VERSION 5.7 ;
BUSBITCHARS "[]" ;
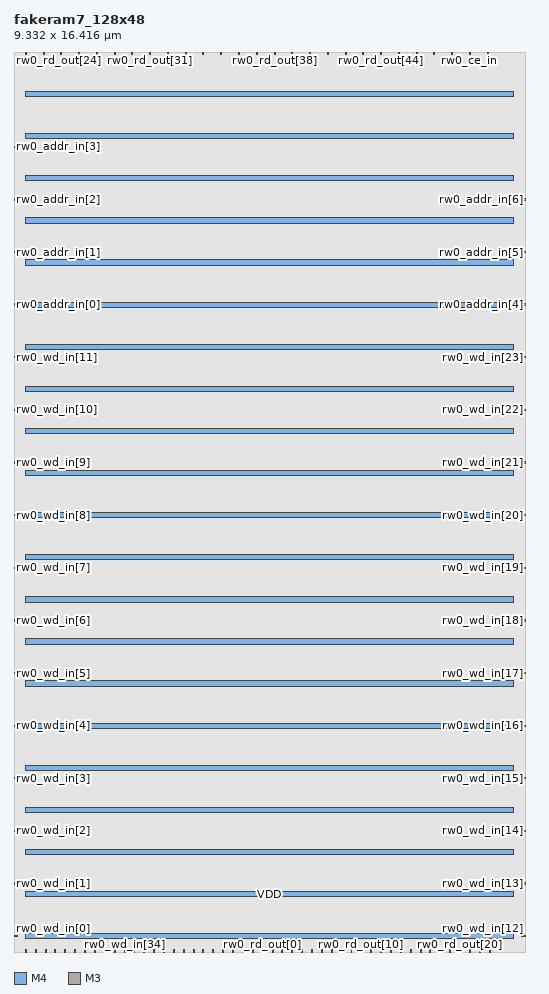
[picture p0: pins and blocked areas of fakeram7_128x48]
MACRO fakeram7_128x48
  FOREIGN fakeram7_128x48 0 0 ;
  SYMMETRY X Y R90 ;
  SIZE 9.332 BY 16.416 ;
  CLASS BLOCK ;
  PIN rw0_wd_in[0]
    DIRECTION INPUT ;
    USE SIGNAL ;
    SHAPE ABUTMENT ;
    PORT
      LAYER M4 ;
      RECT 0.000 0.276 0.072 0.300 ;
    END
  END rw0_wd_in[0]
  PIN rw0_wd_in[1]
    DIRECTION INPUT ;
    USE SIGNAL ;
    SHAPE ABUTMENT ;
    PORT
      LAYER M4 ;
      RECT 0.000 1.236 0.072 1.260 ;
    END
  END rw0_wd_in[1]
  PIN rw0_wd_in[2]
    DIRECTION INPUT ;
    USE SIGNAL ;
    SHAPE ABUTMENT ;
    PORT
      LAYER M4 ;
      RECT 0.000 2.196 0.072 2.220 ;
    END
  END rw0_wd_in[2]
  PIN rw0_wd_in[3]
    DIRECTION INPUT ;
    USE SIGNAL ;
    SHAPE ABUTMENT ;
    PORT
      LAYER M4 ;
      RECT 0.000 3.156 0.072 3.180 ;
    END
  END rw0_wd_in[3]
  PIN rw0_wd_in[4]
    DIRECTION INPUT ;
    USE SIGNAL ;
    SHAPE ABUTMENT ;
    PORT
      LAYER M4 ;
      RECT 0.000 4.116 0.072 4.140 ;
    END
  END rw0_wd_in[4]
  PIN rw0_wd_in[5]
    DIRECTION INPUT ;
    USE SIGNAL ;
    SHAPE ABUTMENT ;
    PORT
      LAYER M4 ;
      RECT 0.000 5.076 0.072 5.100 ;
    END
  END rw0_wd_in[5]
  PIN rw0_wd_in[6]
    DIRECTION INPUT ;
    USE SIGNAL ;
    SHAPE ABUTMENT ;
    PORT
      LAYER M4 ;
      RECT 0.000 6.036 0.072 6.060 ;
    END
  END rw0_wd_in[6]
  PIN rw0_wd_in[7]
    DIRECTION INPUT ;
    USE SIGNAL ;
    SHAPE ABUTMENT ;
    PORT
      LAYER M4 ;
      RECT 0.000 6.996 0.072 7.020 ;
    END
  END rw0_wd_in[7]
  PIN rw0_wd_in[8]
    DIRECTION INPUT ;
    USE SIGNAL ;
    SHAPE ABUTMENT ;
    PORT
      LAYER M4 ;
      RECT 0.000 7.956 0.072 7.980 ;
    END
  END rw0_wd_in[8]
  PIN rw0_wd_in[9]
    DIRECTION INPUT ;
    USE SIGNAL ;
    SHAPE ABUTMENT ;
    PORT
      LAYER M4 ;
      RECT 0.000 8.916 0.072 8.940 ;
    END
  END rw0_wd_in[9]
  PIN rw0_wd_in[10]
    DIRECTION INPUT ;
    USE SIGNAL ;
    SHAPE ABUTMENT ;
    PORT
      LAYER M4 ;
      RECT 0.000 9.876 0.072 9.900 ;
    END
  END rw0_wd_in[10]
  PIN rw0_wd_in[11]
    DIRECTION INPUT ;
    USE SIGNAL ;
    SHAPE ABUTMENT ;
    PORT
      LAYER M4 ;
      RECT 0.000 10.836 0.072 10.860 ;
    END
  END rw0_wd_in[11]
  PIN rw0_wd_in[12]
    DIRECTION INPUT ;
    USE SIGNAL ;
    SHAPE ABUTMENT ;
    PORT
      LAYER M4 ;
      RECT 9.260 0.276 9.332 0.300 ;
    END
  END rw0_wd_in[12]
  PIN rw0_wd_in[13]
    DIRECTION INPUT ;
    USE SIGNAL ;
    SHAPE ABUTMENT ;
    PORT
      LAYER M4 ;
      RECT 9.260 1.236 9.332 1.260 ;
    END
  END rw0_wd_in[13]
  PIN rw0_wd_in[14]
    DIRECTION INPUT ;
    USE SIGNAL ;
    SHAPE ABUTMENT ;
    PORT
      LAYER M4 ;
      RECT 9.260 2.196 9.332 2.220 ;
    END
  END rw0_wd_in[14]
  PIN rw0_wd_in[15]
    DIRECTION INPUT ;
    USE SIGNAL ;
    SHAPE ABUTMENT ;
    PORT
      LAYER M4 ;
      RECT 9.260 3.156 9.332 3.180 ;
    END
  END rw0_wd_in[15]
  PIN rw0_wd_in[16]
    DIRECTION INPUT ;
    USE SIGNAL ;
    SHAPE ABUTMENT ;
    PORT
      LAYER M4 ;
      RECT 9.260 4.116 9.332 4.140 ;
    END
  END rw0_wd_in[16]
  PIN rw0_wd_in[17]
    DIRECTION INPUT ;
    USE SIGNAL ;
    SHAPE ABUTMENT ;
    PORT
      LAYER M4 ;
      RECT 9.260 5.076 9.332 5.100 ;
    END
  END rw0_wd_in[17]
  PIN rw0_wd_in[18]
    DIRECTION INPUT ;
    USE SIGNAL ;
    SHAPE ABUTMENT ;
    PORT
      LAYER M4 ;
      RECT 9.260 6.036 9.332 6.060 ;
    END
  END rw0_wd_in[18]
  PIN rw0_wd_in[19]
    DIRECTION INPUT ;
    USE SIGNAL ;
    SHAPE ABUTMENT ;
    PORT
      LAYER M4 ;
      RECT 9.260 6.996 9.332 7.020 ;
    END
  END rw0_wd_in[19]
  PIN rw0_wd_in[20]
    DIRECTION INPUT ;
    USE SIGNAL ;
    SHAPE ABUTMENT ;
    PORT
      LAYER M4 ;
      RECT 9.260 7.956 9.332 7.980 ;
    END
  END rw0_wd_in[20]
  PIN rw0_wd_in[21]
    DIRECTION INPUT ;
    USE SIGNAL ;
    SHAPE ABUTMENT ;
    PORT
      LAYER M4 ;
      RECT 9.260 8.916 9.332 8.940 ;
    END
  END rw0_wd_in[21]
  PIN rw0_wd_in[22]
    DIRECTION INPUT ;
    USE SIGNAL ;
    SHAPE ABUTMENT ;
    PORT
      LAYER M4 ;
      RECT 9.260 9.876 9.332 9.900 ;
    END
  END rw0_wd_in[22]
  PIN rw0_wd_in[23]
    DIRECTION INPUT ;
    USE SIGNAL ;
    SHAPE ABUTMENT ;
    PORT
      LAYER M4 ;
      RECT 9.260 10.836 9.332 10.860 ;
    END
  END rw0_wd_in[23]
  PIN rw0_wd_in[24]
    DIRECTION OUTPUT ;
    USE SIGNAL ;
    SHAPE ABUTMENT ;
    PORT
      LAYER M3 ;
      RECT 0.207 0.000 0.225 0.054 ;
    END
  END rw0_wd_in[24]
  PIN rw0_wd_in[25]
    DIRECTION OUTPUT ;
    USE SIGNAL ;
    SHAPE ABUTMENT ;
    PORT
      LAYER M3 ;
      RECT 0.387 0.000 0.405 0.054 ;
    END
  END rw0_wd_in[25]
  PIN rw0_wd_in[26]
    DIRECTION OUTPUT ;
    USE SIGNAL ;
    SHAPE ABUTMENT ;
    PORT
      LAYER M3 ;
      RECT 0.567 0.000 0.585 0.054 ;
    END
  END rw0_wd_in[26]
  PIN rw0_wd_in[27]
    DIRECTION OUTPUT ;
    USE SIGNAL ;
    SHAPE ABUTMENT ;
    PORT
      LAYER M3 ;
      RECT 0.747 0.000 0.765 0.054 ;
    END
  END rw0_wd_in[27]
  PIN rw0_wd_in[28]
    DIRECTION OUTPUT ;
    USE SIGNAL ;
    SHAPE ABUTMENT ;
    PORT
      LAYER M3 ;
      RECT 0.927 0.000 0.945 0.054 ;
    END
  END rw0_wd_in[28]
  PIN rw0_wd_in[29]
    DIRECTION OUTPUT ;
    USE SIGNAL ;
    SHAPE ABUTMENT ;
    PORT
      LAYER M3 ;
      RECT 1.107 0.000 1.125 0.054 ;
    END
  END rw0_wd_in[29]
  PIN rw0_wd_in[30]
    DIRECTION OUTPUT ;
    USE SIGNAL ;
    SHAPE ABUTMENT ;
    PORT
      LAYER M3 ;
      RECT 1.287 0.000 1.305 0.054 ;
    END
  END rw0_wd_in[30]
  PIN rw0_wd_in[31]
    DIRECTION OUTPUT ;
    USE SIGNAL ;
    SHAPE ABUTMENT ;
    PORT
      LAYER M3 ;
      RECT 1.467 0.000 1.485 0.054 ;
    END
  END rw0_wd_in[31]
  PIN rw0_wd_in[32]
    DIRECTION OUTPUT ;
    USE SIGNAL ;
    SHAPE ABUTMENT ;
    PORT
      LAYER M3 ;
      RECT 1.647 0.000 1.665 0.054 ;
    END
  END rw0_wd_in[32]
  PIN rw0_wd_in[33]
    DIRECTION OUTPUT ;
    USE SIGNAL ;
    SHAPE ABUTMENT ;
    PORT
      LAYER M3 ;
      RECT 1.827 0.000 1.845 0.054 ;
    END
  END rw0_wd_in[33]
  PIN rw0_wd_in[34]
    DIRECTION OUTPUT ;
    USE SIGNAL ;
    SHAPE ABUTMENT ;
    PORT
      LAYER M3 ;
      RECT 2.007 0.000 2.025 0.054 ;
    END
  END rw0_wd_in[34]
  PIN rw0_wd_in[35]
    DIRECTION OUTPUT ;
    USE SIGNAL ;
    SHAPE ABUTMENT ;
    PORT
      LAYER M3 ;
      RECT 2.187 0.000 2.205 0.054 ;
    END
  END rw0_wd_in[35]
  PIN rw0_wd_in[36]
    DIRECTION OUTPUT ;
    USE SIGNAL ;
    SHAPE ABUTMENT ;
    PORT
      LAYER M3 ;
      RECT 2.367 0.000 2.385 0.054 ;
    END
  END rw0_wd_in[36]
  PIN rw0_wd_in[37]
    DIRECTION OUTPUT ;
    USE SIGNAL ;
    SHAPE ABUTMENT ;
    PORT
      LAYER M3 ;
      RECT 2.547 0.000 2.565 0.054 ;
    END
  END rw0_wd_in[37]
  PIN rw0_wd_in[38]
    DIRECTION OUTPUT ;
    USE SIGNAL ;
    SHAPE ABUTMENT ;
    PORT
      LAYER M3 ;
      RECT 2.727 0.000 2.745 0.054 ;
    END
  END rw0_wd_in[38]
  PIN rw0_wd_in[39]
    DIRECTION OUTPUT ;
    USE SIGNAL ;
    SHAPE ABUTMENT ;
    PORT
      LAYER M3 ;
      RECT 2.907 0.000 2.925 0.054 ;
    END
  END rw0_wd_in[39]
  PIN rw0_wd_in[40]
    DIRECTION OUTPUT ;
    USE SIGNAL ;
    SHAPE ABUTMENT ;
    PORT
      LAYER M3 ;
      RECT 3.087 0.000 3.105 0.054 ;
    END
  END rw0_wd_in[40]
  PIN rw0_wd_in[41]
    DIRECTION OUTPUT ;
    USE SIGNAL ;
    SHAPE ABUTMENT ;
    PORT
      LAYER M3 ;
      RECT 3.267 0.000 3.285 0.054 ;
    END
  END rw0_wd_in[41]
  PIN rw0_wd_in[42]
    DIRECTION OUTPUT ;
    USE SIGNAL ;
    SHAPE ABUTMENT ;
    PORT
      LAYER M3 ;
      RECT 3.447 0.000 3.465 0.054 ;
    END
  END rw0_wd_in[42]
  PIN rw0_wd_in[43]
    DIRECTION OUTPUT ;
    USE SIGNAL ;
    SHAPE ABUTMENT ;
    PORT
      LAYER M3 ;
      RECT 3.627 0.000 3.645 0.054 ;
    END
  END rw0_wd_in[43]
  PIN rw0_wd_in[44]
    DIRECTION OUTPUT ;
    USE SIGNAL ;
    SHAPE ABUTMENT ;
    PORT
      LAYER M3 ;
      RECT 3.807 0.000 3.825 0.054 ;
    END
  END rw0_wd_in[44]
  PIN rw0_wd_in[45]
    DIRECTION OUTPUT ;
    USE SIGNAL ;
    SHAPE ABUTMENT ;
    PORT
      LAYER M3 ;
      RECT 3.987 0.000 4.005 0.054 ;
    END
  END rw0_wd_in[45]
  PIN rw0_wd_in[46]
    DIRECTION OUTPUT ;
    USE SIGNAL ;
    SHAPE ABUTMENT ;
    PORT
      LAYER M3 ;
      RECT 4.167 0.000 4.185 0.054 ;
    END
  END rw0_wd_in[46]
  PIN rw0_wd_in[47]
    DIRECTION OUTPUT ;
    USE SIGNAL ;
    SHAPE ABUTMENT ;
    PORT
      LAYER M3 ;
      RECT 4.347 0.000 4.365 0.054 ;
    END
  END rw0_wd_in[47]
  PIN rw0_rd_out[0]
    DIRECTION OUTPUT ;
    USE SIGNAL ;
    SHAPE ABUTMENT ;
    PORT
      LAYER M3 ;
      RECT 4.527 0.000 4.545 0.054 ;
    END
  END rw0_rd_out[0]
  PIN rw0_rd_out[1]
    DIRECTION OUTPUT ;
    USE SIGNAL ;
    SHAPE ABUTMENT ;
    PORT
      LAYER M3 ;
      RECT 4.707 0.000 4.725 0.054 ;
    END
  END rw0_rd_out[1]
  PIN rw0_rd_out[2]
    DIRECTION OUTPUT ;
    USE SIGNAL ;
    SHAPE ABUTMENT ;
    PORT
      LAYER M3 ;
      RECT 4.887 0.000 4.905 0.054 ;
    END
  END rw0_rd_out[2]
  PIN rw0_rd_out[3]
    DIRECTION OUTPUT ;
    USE SIGNAL ;
    SHAPE ABUTMENT ;
    PORT
      LAYER M3 ;
      RECT 5.067 0.000 5.085 0.054 ;
    END
  END rw0_rd_out[3]
  PIN rw0_rd_out[4]
    DIRECTION OUTPUT ;
    USE SIGNAL ;
    SHAPE ABUTMENT ;
    PORT
      LAYER M3 ;
      RECT 5.247 0.000 5.265 0.054 ;
    END
  END rw0_rd_out[4]
  PIN rw0_rd_out[5]
    DIRECTION OUTPUT ;
    USE SIGNAL ;
    SHAPE ABUTMENT ;
    PORT
      LAYER M3 ;
      RECT 5.427 0.000 5.445 0.054 ;
    END
  END rw0_rd_out[5]
  PIN rw0_rd_out[6]
    DIRECTION OUTPUT ;
    USE SIGNAL ;
    SHAPE ABUTMENT ;
    PORT
      LAYER M3 ;
      RECT 5.607 0.000 5.625 0.054 ;
    END
  END rw0_rd_out[6]
  PIN rw0_rd_out[7]
    DIRECTION OUTPUT ;
    USE SIGNAL ;
    SHAPE ABUTMENT ;
    PORT
      LAYER M3 ;
      RECT 5.787 0.000 5.805 0.054 ;
    END
  END rw0_rd_out[7]
  PIN rw0_rd_out[8]
    DIRECTION OUTPUT ;
    USE SIGNAL ;
    SHAPE ABUTMENT ;
    PORT
      LAYER M3 ;
      RECT 5.967 0.000 5.985 0.054 ;
    END
  END rw0_rd_out[8]
  PIN rw0_rd_out[9]
    DIRECTION OUTPUT ;
    USE SIGNAL ;
    SHAPE ABUTMENT ;
    PORT
      LAYER M3 ;
      RECT 6.147 0.000 6.165 0.054 ;
    END
  END rw0_rd_out[9]
  PIN rw0_rd_out[10]
    DIRECTION OUTPUT ;
    USE SIGNAL ;
    SHAPE ABUTMENT ;
    PORT
      LAYER M3 ;
      RECT 6.327 0.000 6.345 0.054 ;
    END
  END rw0_rd_out[10]
  PIN rw0_rd_out[11]
    DIRECTION OUTPUT ;
    USE SIGNAL ;
    SHAPE ABUTMENT ;
    PORT
      LAYER M3 ;
      RECT 6.507 0.000 6.525 0.054 ;
    END
  END rw0_rd_out[11]
  PIN rw0_rd_out[12]
    DIRECTION OUTPUT ;
    USE SIGNAL ;
    SHAPE ABUTMENT ;
    PORT
      LAYER M3 ;
      RECT 6.687 0.000 6.705 0.054 ;
    END
  END rw0_rd_out[12]
  PIN rw0_rd_out[13]
    DIRECTION OUTPUT ;
    USE SIGNAL ;
    SHAPE ABUTMENT ;
    PORT
      LAYER M3 ;
      RECT 6.867 0.000 6.885 0.054 ;
    END
  END rw0_rd_out[13]
  PIN rw0_rd_out[14]
    DIRECTION OUTPUT ;
    USE SIGNAL ;
    SHAPE ABUTMENT ;
    PORT
      LAYER M3 ;
      RECT 7.047 0.000 7.065 0.054 ;
    END
  END rw0_rd_out[14]
  PIN rw0_rd_out[15]
    DIRECTION OUTPUT ;
    USE SIGNAL ;
    SHAPE ABUTMENT ;
    PORT
      LAYER M3 ;
      RECT 7.227 0.000 7.245 0.054 ;
    END
  END rw0_rd_out[15]
  PIN rw0_rd_out[16]
    DIRECTION OUTPUT ;
    USE SIGNAL ;
    SHAPE ABUTMENT ;
    PORT
      LAYER M3 ;
      RECT 7.407 0.000 7.425 0.054 ;
    END
  END rw0_rd_out[16]
  PIN rw0_rd_out[17]
    DIRECTION OUTPUT ;
    USE SIGNAL ;
    SHAPE ABUTMENT ;
    PORT
      LAYER M3 ;
      RECT 7.587 0.000 7.605 0.054 ;
    END
  END rw0_rd_out[17]
  PIN rw0_rd_out[18]
    DIRECTION OUTPUT ;
    USE SIGNAL ;
    SHAPE ABUTMENT ;
    PORT
      LAYER M3 ;
      RECT 7.767 0.000 7.785 0.054 ;
    END
  END rw0_rd_out[18]
  PIN rw0_rd_out[19]
    DIRECTION OUTPUT ;
    USE SIGNAL ;
    SHAPE ABUTMENT ;
    PORT
      LAYER M3 ;
      RECT 7.947 0.000 7.965 0.054 ;
    END
  END rw0_rd_out[19]
  PIN rw0_rd_out[20]
    DIRECTION OUTPUT ;
    USE SIGNAL ;
    SHAPE ABUTMENT ;
    PORT
      LAYER M3 ;
      RECT 8.127 0.000 8.145 0.054 ;
    END
  END rw0_rd_out[20]
  PIN rw0_rd_out[21]
    DIRECTION OUTPUT ;
    USE SIGNAL ;
    SHAPE ABUTMENT ;
    PORT
      LAYER M3 ;
      RECT 8.307 0.000 8.325 0.054 ;
    END
  END rw0_rd_out[21]
  PIN rw0_rd_out[22]
    DIRECTION OUTPUT ;
    USE SIGNAL ;
    SHAPE ABUTMENT ;
    PORT
      LAYER M3 ;
      RECT 8.487 0.000 8.505 0.054 ;
    END
  END rw0_rd_out[22]
  PIN rw0_rd_out[23]
    DIRECTION OUTPUT ;
    USE SIGNAL ;
    SHAPE ABUTMENT ;
    PORT
      LAYER M3 ;
      RECT 8.667 0.000 8.685 0.054 ;
    END
  END rw0_rd_out[23]
  PIN rw0_rd_out[24]
    DIRECTION OUTPUT ;
    USE SIGNAL ;
    SHAPE ABUTMENT ;
    PORT
      LAYER M3 ;
      RECT 0.207 16.362 0.225 16.416 ;
    END
  END rw0_rd_out[24]
  PIN rw0_rd_out[25]
    DIRECTION OUTPUT ;
    USE SIGNAL ;
    SHAPE ABUTMENT ;
    PORT
      LAYER M3 ;
      RECT 0.531 16.362 0.549 16.416 ;
    END
  END rw0_rd_out[25]
  PIN rw0_rd_out[26]
    DIRECTION OUTPUT ;
    USE SIGNAL ;
    SHAPE ABUTMENT ;
    PORT
      LAYER M3 ;
      RECT 0.855 16.362 0.873 16.416 ;
    END
  END rw0_rd_out[26]
  PIN rw0_rd_out[27]
    DIRECTION OUTPUT ;
    USE SIGNAL ;
    SHAPE ABUTMENT ;
    PORT
      LAYER M3 ;
      RECT 1.179 16.362 1.197 16.416 ;
    END
  END rw0_rd_out[27]
  PIN rw0_rd_out[28]
    DIRECTION OUTPUT ;
    USE SIGNAL ;
    SHAPE ABUTMENT ;
    PORT
      LAYER M3 ;
      RECT 1.503 16.362 1.521 16.416 ;
    END
  END rw0_rd_out[28]
  PIN rw0_rd_out[29]
    DIRECTION OUTPUT ;
    USE SIGNAL ;
    SHAPE ABUTMENT ;
    PORT
      LAYER M3 ;
      RECT 1.827 16.362 1.845 16.416 ;
    END
  END rw0_rd_out[29]
  PIN rw0_rd_out[30]
    DIRECTION OUTPUT ;
    USE SIGNAL ;
    SHAPE ABUTMENT ;
    PORT
      LAYER M3 ;
      RECT 2.151 16.362 2.169 16.416 ;
    END
  END rw0_rd_out[30]
  PIN rw0_rd_out[31]
    DIRECTION OUTPUT ;
    USE SIGNAL ;
    SHAPE ABUTMENT ;
    PORT
      LAYER M3 ;
      RECT 2.475 16.362 2.493 16.416 ;
    END
  END rw0_rd_out[31]
  PIN rw0_rd_out[32]
    DIRECTION OUTPUT ;
    USE SIGNAL ;
    SHAPE ABUTMENT ;
    PORT
      LAYER M3 ;
      RECT 2.799 16.362 2.817 16.416 ;
    END
  END rw0_rd_out[32]
  PIN rw0_rd_out[33]
    DIRECTION OUTPUT ;
    USE SIGNAL ;
    SHAPE ABUTMENT ;
    PORT
      LAYER M3 ;
      RECT 3.123 16.362 3.141 16.416 ;
    END
  END rw0_rd_out[33]
  PIN rw0_rd_out[34]
    DIRECTION OUTPUT ;
    USE SIGNAL ;
    SHAPE ABUTMENT ;
    PORT
      LAYER M3 ;
      RECT 3.447 16.362 3.465 16.416 ;
    END
  END rw0_rd_out[34]
  PIN rw0_rd_out[35]
    DIRECTION OUTPUT ;
    USE SIGNAL ;
    SHAPE ABUTMENT ;
    PORT
      LAYER M3 ;
      RECT 3.771 16.362 3.789 16.416 ;
    END
  END rw0_rd_out[35]
  PIN rw0_rd_out[36]
    DIRECTION OUTPUT ;
    USE SIGNAL ;
    SHAPE ABUTMENT ;
    PORT
      LAYER M3 ;
      RECT 4.095 16.362 4.113 16.416 ;
    END
  END rw0_rd_out[36]
  PIN rw0_rd_out[37]
    DIRECTION OUTPUT ;
    USE SIGNAL ;
    SHAPE ABUTMENT ;
    PORT
      LAYER M3 ;
      RECT 4.419 16.362 4.437 16.416 ;
    END
  END rw0_rd_out[37]
  PIN rw0_rd_out[38]
    DIRECTION OUTPUT ;
    USE SIGNAL ;
    SHAPE ABUTMENT ;
    PORT
      LAYER M3 ;
      RECT 4.743 16.362 4.761 16.416 ;
    END
  END rw0_rd_out[38]
  PIN rw0_rd_out[39]
    DIRECTION OUTPUT ;
    USE SIGNAL ;
    SHAPE ABUTMENT ;
    PORT
      LAYER M3 ;
      RECT 5.067 16.362 5.085 16.416 ;
    END
  END rw0_rd_out[39]
  PIN rw0_rd_out[40]
    DIRECTION OUTPUT ;
    USE SIGNAL ;
    SHAPE ABUTMENT ;
    PORT
      LAYER M3 ;
      RECT 5.391 16.362 5.409 16.416 ;
    END
  END rw0_rd_out[40]
  PIN rw0_rd_out[41]
    DIRECTION OUTPUT ;
    USE SIGNAL ;
    SHAPE ABUTMENT ;
    PORT
      LAYER M3 ;
      RECT 5.715 16.362 5.733 16.416 ;
    END
  END rw0_rd_out[41]
  PIN rw0_rd_out[42]
    DIRECTION OUTPUT ;
    USE SIGNAL ;
    SHAPE ABUTMENT ;
    PORT
      LAYER M3 ;
      RECT 6.039 16.362 6.057 16.416 ;
    END
  END rw0_rd_out[42]
  PIN rw0_rd_out[43]
    DIRECTION OUTPUT ;
    USE SIGNAL ;
    SHAPE ABUTMENT ;
    PORT
      LAYER M3 ;
      RECT 6.363 16.362 6.381 16.416 ;
    END
  END rw0_rd_out[43]
  PIN rw0_rd_out[44]
    DIRECTION OUTPUT ;
    USE SIGNAL ;
    SHAPE ABUTMENT ;
    PORT
      LAYER M3 ;
      RECT 6.687 16.362 6.705 16.416 ;
    END
  END rw0_rd_out[44]
  PIN rw0_rd_out[45]
    DIRECTION OUTPUT ;
    USE SIGNAL ;
    SHAPE ABUTMENT ;
    PORT
      LAYER M3 ;
      RECT 7.011 16.362 7.029 16.416 ;
    END
  END rw0_rd_out[45]
  PIN rw0_rd_out[46]
    DIRECTION OUTPUT ;
    USE SIGNAL ;
    SHAPE ABUTMENT ;
    PORT
      LAYER M3 ;
      RECT 7.335 16.362 7.353 16.416 ;
    END
  END rw0_rd_out[46]
  PIN rw0_rd_out[47]
    DIRECTION OUTPUT ;
    USE SIGNAL ;
    SHAPE ABUTMENT ;
    PORT
      LAYER M3 ;
      RECT 7.659 16.362 7.677 16.416 ;
    END
  END rw0_rd_out[47]
  PIN rw0_addr_in[0]
    DIRECTION INPUT ;
    USE SIGNAL ;
    SHAPE ABUTMENT ;
    PORT
      LAYER M4 ;
      RECT 0.000 11.796 0.072 11.820 ;
    END
  END rw0_addr_in[0]
  PIN rw0_addr_in[1]
    DIRECTION INPUT ;
    USE SIGNAL ;
    SHAPE ABUTMENT ;
    PORT
      LAYER M4 ;
      RECT 0.000 12.756 0.072 12.780 ;
    END
  END rw0_addr_in[1]
  PIN rw0_addr_in[2]
    DIRECTION INPUT ;
    USE SIGNAL ;
    SHAPE ABUTMENT ;
    PORT
      LAYER M4 ;
      RECT 0.000 13.716 0.072 13.740 ;
    END
  END rw0_addr_in[2]
  PIN rw0_addr_in[3]
    DIRECTION INPUT ;
    USE SIGNAL ;
    SHAPE ABUTMENT ;
    PORT
      LAYER M4 ;
      RECT 0.000 14.676 0.072 14.700 ;
    END
  END rw0_addr_in[3]
  PIN rw0_addr_in[4]
    DIRECTION INPUT ;
    USE SIGNAL ;
    SHAPE ABUTMENT ;
    PORT
      LAYER M4 ;
      RECT 9.260 11.796 9.332 11.820 ;
    END
  END rw0_addr_in[4]
  PIN rw0_addr_in[5]
    DIRECTION INPUT ;
    USE SIGNAL ;
    SHAPE ABUTMENT ;
    PORT
      LAYER M4 ;
      RECT 9.260 12.756 9.332 12.780 ;
    END
  END rw0_addr_in[5]
  PIN rw0_addr_in[6]
    DIRECTION INPUT ;
    USE SIGNAL ;
    SHAPE ABUTMENT ;
    PORT
      LAYER M4 ;
      RECT 9.260 13.716 9.332 13.740 ;
    END
  END rw0_addr_in[6]
  PIN rw0_we_in
    DIRECTION INPUT ;
    USE SIGNAL ;
    SHAPE ABUTMENT ;
    PORT
      LAYER M3 ;
      RECT 7.983 16.362 8.001 16.416 ;
    END
  END rw0_we_in
  PIN rw0_ce_in
    DIRECTION INPUT ;
    USE SIGNAL ;
    SHAPE ABUTMENT ;
    PORT
      LAYER M3 ;
      RECT 8.307 16.362 8.325 16.416 ;
    END
  END rw0_ce_in
  PIN rw0_clk
    DIRECTION INPUT ;
    USE SIGNAL ;
    SHAPE ABUTMENT ;
    PORT
      LAYER M3 ;
      RECT 8.631 16.362 8.649 16.416 ;
    END
  END rw0_clk
  PIN VSS
    DIRECTION INOUT ;
    USE GROUND ;
    PORT
      LAYER M4 ;
      RECT 0.216 0.240 9.116 0.336 ;
      RECT 0.216 1.008 9.116 1.104 ;
      RECT 0.216 1.776 9.116 1.872 ;
      RECT 0.216 2.544 9.116 2.640 ;
      RECT 0.216 3.312 9.116 3.408 ;
      RECT 0.216 4.080 9.116 4.176 ;
      RECT 0.216 4.848 9.116 4.944 ;
      RECT 0.216 5.616 9.116 5.712 ;
      RECT 0.216 6.384 9.116 6.480 ;
      RECT 0.216 7.152 9.116 7.248 ;
      RECT 0.216 7.920 9.116 8.016 ;
      RECT 0.216 8.688 9.116 8.784 ;
      RECT 0.216 9.456 9.116 9.552 ;
      RECT 0.216 10.224 9.116 10.320 ;
      RECT 0.216 10.992 9.116 11.088 ;
      RECT 0.216 11.760 9.116 11.856 ;
      RECT 0.216 12.528 9.116 12.624 ;
      RECT 0.216 13.296 9.116 13.392 ;
      RECT 0.216 14.064 9.116 14.160 ;
      RECT 0.216 14.832 9.116 14.928 ;
      RECT 0.216 15.600 9.116 15.696 ;
    END
  END VSS
  PIN VDD
    DIRECTION INOUT ;
    USE POWER ;
    PORT
      LAYER M4 ;
      RECT 0.216 0.240 9.116 0.336 ;
      RECT 0.216 1.008 9.116 1.104 ;
      RECT 0.216 1.776 9.116 1.872 ;
      RECT 0.216 2.544 9.116 2.640 ;
      RECT 0.216 3.312 9.116 3.408 ;
      RECT 0.216 4.080 9.116 4.176 ;
      RECT 0.216 4.848 9.116 4.944 ;
      RECT 0.216 5.616 9.116 5.712 ;
      RECT 0.216 6.384 9.116 6.480 ;
      RECT 0.216 7.152 9.116 7.248 ;
      RECT 0.216 7.920 9.116 8.016 ;
      RECT 0.216 8.688 9.116 8.784 ;
      RECT 0.216 9.456 9.116 9.552 ;
      RECT 0.216 10.224 9.116 10.320 ;
      RECT 0.216 10.992 9.116 11.088 ;
      RECT 0.216 11.760 9.116 11.856 ;
      RECT 0.216 12.528 9.116 12.624 ;
      RECT 0.216 13.296 9.116 13.392 ;
      RECT 0.216 14.064 9.116 14.160 ;
      RECT 0.216 14.832 9.116 14.928 ;
      RECT 0.216 15.600 9.116 15.696 ;
    END
  END VDD
  OBS
    LAYER M1 ;
    RECT 0 0 9.332 16.416 ;
    LAYER M2 ;
    RECT 0 0 9.332 16.416 ;
    LAYER M3 ;
    RECT 0 0 9.332 16.416 ;
    LAYER M4 ;
    RECT 0 0 9.332 16.416 ;
  END
END fakeram7_128x48

END LIBRARY
